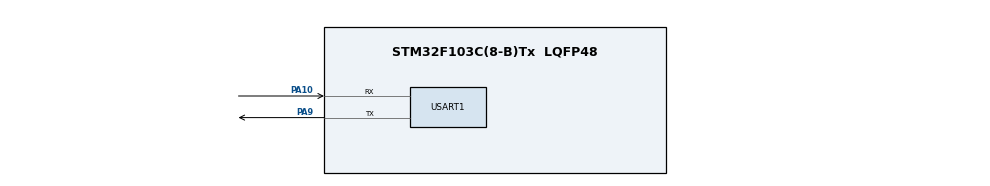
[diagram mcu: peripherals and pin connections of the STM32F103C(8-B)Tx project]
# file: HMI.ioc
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Mcu.Family=STM32F1
Mcu.Name=STM32F103C(8-B)Tx
Mcu.Package=LQFP48
NVIC.PriorityGroup=NVIC_PRIORITYGROUP_4
PA10.Mode=Asynchronous
PA10.Signal=USART1_RX
PA13.Mode=Serial_Wire
PA13.Signal=SYS_JTMS-SWDIO
PA14.Mode=Serial_Wire
PA14.Signal=SYS_JTCK-SWCLK
PA9.Mode=Asynchronous
PA9.Signal=USART1_TX
PD0-OSC_IN.Mode=HSE-External-Oscillator
PD0-OSC_IN.Signal=RCC_OSC_IN
PD1-OSC_OUT.Mode=HSE-External-Oscillator
PD1-OSC_OUT.Signal=RCC_OSC_OUT
ProjectManager.HeapSize=0x200
ProjectManager.StackSize=0x400
ProjectManager.TargetToolchain=STM32CubeIDE
RCC.APB1Freq_Value=8000000
RCC.APB2Freq_Value=8000000
USART1.VirtualMode=VM_ASYNC
board=custom

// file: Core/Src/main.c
/* USER CODE BEGIN Header */
/**
  ******************************************************************************
  * @file           : main.c
  * @brief          : Main program body
  ******************************************************************************
  * @attention
  *
  * <h2><center>&copy; Copyright (c) 2020 STMicroelectronics.
  * All rights reserved.</center></h2>
  *
  * This software component is licensed by ST under BSD 3-Clause license,
  * the "License"; You may not use this file except in compliance with the
  * License. You may obtain a copy of the License at:
  *                        opensource.org/licenses/BSD-3-Clause
  *
  ******************************************************************************
  */
/* USER CODE END Header */

#include "main.h"

/* USER CODE BEGIN Includes */
#include "stdio.h"
/* USER CODE END Includes */

UART_HandleTypeDef huart1;

void SystemClock_Config(void);
static void MX_GPIO_Init(void);
static void MX_USART1_UART_Init(void);

/* USER CODE BEGIN 0 */

uint8_t Cmd_End[3] = {0xFF,0xFF,0xFF};  // command end sequence

void NEXTION_SendString (char *ID, char *string)
{
	char buf[50];
	int len = sprintf (buf, "%s.txt=\"%s\"", ID, string);
	HAL_UART_Transmit(&huart1, (uint8_t *)buf, len, 1000);
	HAL_UART_Transmit(&huart1, Cmd_End, 3, 100);
	HAL_Delay (1000);
}

/* USER CODE END 0 */

int main(void)
{

  /* MCU Configuration--------------------------------------------------------*/

  /* Reset of all peripherals, Initializes the Flash interface and the Systick. */
  HAL_Init();

  /* Configure the system clock */
  SystemClock_Config();

  /* Initialize all configured peripherals */
  MX_GPIO_Init();
  MX_USART1_UART_Init();
  /* USER CODE BEGIN 2 */

  uint8_t data[30]={};
  /* USER CODE END 2 */

  /* Infinite loop */
  while (1)
  {
    /* USER CODE BEGIN 3 */
	  NEXTION_SendString("t0", "Hello");
	  NEXTION_SendString("t0", "World");
  }
  /* USER CODE END 3 */
}
//	  NEXTION_SendString("t0", "From");
//	  NEXTION_SendString("t1", "CTech");
//HAL_UART_Receive(&huart1, data, 30, 1000);
void SystemClock_Config(void)
{
  RCC_OscInitTypeDef RCC_OscInitStruct = {0};
  RCC_ClkInitTypeDef RCC_ClkInitStruct = {0};

  /** Initializes the CPU, AHB and APB busses clocks
  */
  RCC_OscInitStruct.OscillatorType = RCC_OSCILLATORTYPE_HSE;
  RCC_OscInitStruct.HSEState = RCC_HSE_ON;
  RCC_OscInitStruct.HSEPredivValue = RCC_HSE_PREDIV_DIV1;
  RCC_OscInitStruct.HSIState = RCC_HSI_ON;
  RCC_OscInitStruct.PLL.PLLState = RCC_PLL_ON;
  RCC_OscInitStruct.PLL.PLLSource = RCC_PLLSOURCE_HSE;
  RCC_OscInitStruct.PLL.PLLMUL = RCC_PLL_MUL9;
  if (HAL_RCC_OscConfig(&RCC_OscInitStruct) != HAL_OK)
  {
    Error_Handler();
  }
  /** Initializes the CPU, AHB and APB busses clocks
  */
  RCC_ClkInitStruct.ClockType = RCC_CLOCKTYPE_HCLK|RCC_CLOCKTYPE_SYSCLK
                              |RCC_CLOCKTYPE_PCLK1|RCC_CLOCKTYPE_PCLK2;
  RCC_ClkInitStruct.SYSCLKSource = RCC_SYSCLKSOURCE_PLLCLK;
  RCC_ClkInitStruct.AHBCLKDivider = RCC_SYSCLK_DIV1;
  RCC_ClkInitStruct.APB1CLKDivider = RCC_HCLK_DIV2;
  RCC_ClkInitStruct.APB2CLKDivider = RCC_HCLK_DIV1;

  if (HAL_RCC_ClockConfig(&RCC_ClkInitStruct, FLASH_LATENCY_2) != HAL_OK)
  {
    Error_Handler();
  }
}

static void MX_USART1_UART_Init(void)
{

  huart1.Instance = USART1;
  huart1.Init.BaudRate = 9600;
  huart1.Init.WordLength = UART_WORDLENGTH_8B;
  huart1.Init.StopBits = UART_STOPBITS_1;
  huart1.Init.Parity = UART_PARITY_NONE;
  huart1.Init.Mode = UART_MODE_TX_RX;
  huart1.Init.HwFlowCtl = UART_HWCONTROL_NONE;
  huart1.Init.OverSampling = UART_OVERSAMPLING_16;
  if (HAL_UART_Init(&huart1) != HAL_OK)
  {
    Error_Handler();
  }

}

static void MX_GPIO_Init(void)
{

  /* GPIO Ports Clock Enable */
  __HAL_RCC_GPIOD_CLK_ENABLE();
  __HAL_RCC_GPIOA_CLK_ENABLE();

}

void Error_Handler(void)
{
}

/************************ (C) COPYRIGHT STMicroelectronics *****END OF FILE****/
